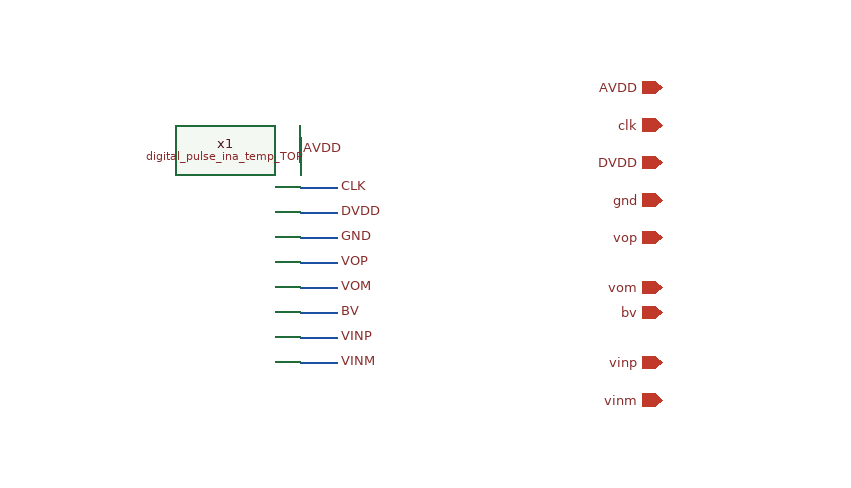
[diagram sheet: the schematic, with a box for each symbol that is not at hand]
v {xschem version=3.4.6 file_version=1.2}
G {}
K {}
V {}
S {}
E {}
N 420 -10 420 10 {lab=AVDD}
N 420 30 450 30 {lab=CLK}
N 420 50 450 50 {lab=DVDD}
N 420 70 450 70 {lab=GND}
N 420 90 450 90 {lab=VOP}
N 420 110 450 110 {lab=VOM}
N 420 130 450 130 {lab=BV}
N 420 150 450 150 {lab=VINP}
N 420 170 450 170 {lab=VINM}
C {iopin.sym} 710 -20 0 0 {name=p7 lab=clk}
C {iopin.sym} 710 10 0 0 {name=p8 lab=DVDD}
C {iopin.sym} 710 40 0 0 {name=p9 lab=gnd}
C {iopin.sym} 710 70 0 0 {name=p23 lab=vop}
C {iopin.sym} 710 110 0 0 {name=p24 lab=vom}
C {iopin.sym} 710 130 0 0 {name=p29 lab=bv}
C {iopin.sym} 710 170 0 0 {name=p30 lab=vinp}
C {iopin.sym} 710 200 0 0 {name=p10 lab=vinm}
C {iopin.sym} 710 -50 0 0 {name=p31 lab=AVDD}
C {digital_pulse_ina_temp_TOP.sym} 270 80 0 0 {name=x1}
C {devices/lab_pin.sym} 420 0 2 0 {name=p20 sig_type=std_logic lab=AVDD

}
C {devices/lab_pin.sym} 450 50 2 0 {name=p2 sig_type=std_logic lab=DVDD

}
C {devices/lab_pin.sym} 450 70 2 0 {name=p3 sig_type=std_logic lab=GND

}
C {devices/lab_pin.sym} 450 90 2 0 {name=p4 sig_type=std_logic lab=VOP

}
C {devices/lab_pin.sym} 450 110 2 0 {name=p5 sig_type=std_logic lab=VOM

}
C {devices/lab_pin.sym} 450 130 2 0 {name=p6 sig_type=std_logic lab=BV

}
C {devices/lab_pin.sym} 450 150 2 0 {name=p11 sig_type=std_logic lab=VINP

}
C {devices/lab_pin.sym} 450 170 2 0 {name=p12 sig_type=std_logic lab=VINM

}
C {devices/lab_pin.sym} 450 30 2 0 {name=p13 sig_type=std_logic lab=CLK

}
